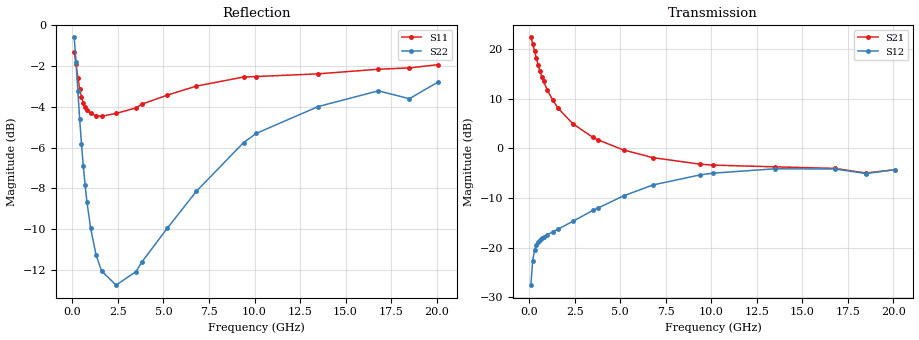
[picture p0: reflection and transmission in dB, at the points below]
!  Infineon Technologies AG
! BFR380L3 , PF131585-7, No.6, Th 09.10.01, soldered on pcb-board, measured with PP GSG850
!  Vce=0.5 V,  Ic=4.0 mA
! Common Emitter S-Parameters:  15. November 2001
#  GHz  S  MA  R  50
! f  S11  S21  S12  S22
! GHz  Mag  Ang  Mag  Ang  Mag  Ang  Mag  Ang
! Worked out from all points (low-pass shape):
!   201 points, 100 MHz to 20.1 GHz, reference 50 ohm
!   highest |S21| = 22.33 dB at 100 MHz (marker M1); lowest = -5.0 dB at 18.5 GHz (marker M2)
!   |S21| within 3 dB of the highest: start of sweep to 317.4 MHz
!   lowest |S11| = -4.5 dB at 1.6 GHz (marker M3), VSWR 3.98, Z = 12.6 - j1.46 ohm
!   |S11| at or under -10 dB: nowhere
!   |S22| runs from -12.8 to -0.6 dB; largest |S21 - S12| = 13
!   S11 on the Smith chart (normalised r, x): 100 MHz: 0.87, -3.15; 400 MHz: 0.29, -0.78; 1 GHz: 0.26, -0.22; 3.8 GHz: 0.25, +0.34; 9.4 GHz: 0.33, +1.11; 20.1 GHz: 0.93, +2.58
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0.1  0.8607 -33.1  13.08 158.9  0.04204 71.6  0.9348 -22.2
0.2  0.8041 -61.6  11.29 141.5  0.07421 58.3  0.8147 -40.6
0.3  0.7449 -84.1  9.537 128.6  0.09425 49.0  0.6906 -54.3
0.4  0.6981 -101.3  8.061 118.8  0.1064 42.8  0.5888 -64.8
0.5  0.6673 -115.0  6.899 111.2  0.1144 38.9  0.5104 -73.1
0.6  0.6438 -125.9  5.987 105.3  0.1205 36.5  0.4508 -79.9
0.7  0.6288 -134.7  5.281 100.2  0.125 34.9  0.4046 -85.6
0.8  0.6211 -142.0  4.709 96.0  0.1286 34.1  0.3683 -90.6
1  0.6077 -153.7  3.873 88.9  0.1353 33.4  0.3178 -98.9
1.3  0.6002 -166.7  3.055 80.3  0.1443 34.1  0.2731 -109.2
1.6  0.5981 -176.4  2.532 73.1  0.1541 35.5  0.2491 -117.7
2.4  0.6078 164.3  1.771 57.5  0.1841 39.3  0.23 -135.5
3.5  0.6273 144.7  1.291 40.4  0.2372 41.8  0.2484 -154.0
3.8  0.6402 140.4  1.213 36.7  0.2515 41.7  0.2616 -159.3
5.2  0.6739 121.5  0.9618 20.9  0.3332 37.7  0.3169 -178.8
6.8  0.7094 103.0  0.806 8.4  0.4279 29.8  0.3908 158.5
9.400001  0.747 81.2  0.6925 -4.7  0.5411 13.1  0.5154 130.1
10.1  0.749 76.3  0.6781 -7.1  0.5625 8.6  0.543 123.0
13.5  0.7605 58.7  0.6517 -20.9  0.6228 -12.2  0.632 94.3
16.8  0.7806 46.9  0.6283 -32.2  0.6195 -27.6  0.6908 73.8
18.5  0.7863 45.2  0.5641 -39.9  0.558 -35.8  0.6607 68.7
20.1  0.8015 38.3  0.6101 -43.6  0.6103 -40.5  0.7268 58.4
